One B-rep face of a CAD part: STEP entity #6673.
In plain terms, the planar face has unit normal (0, 1, 0).
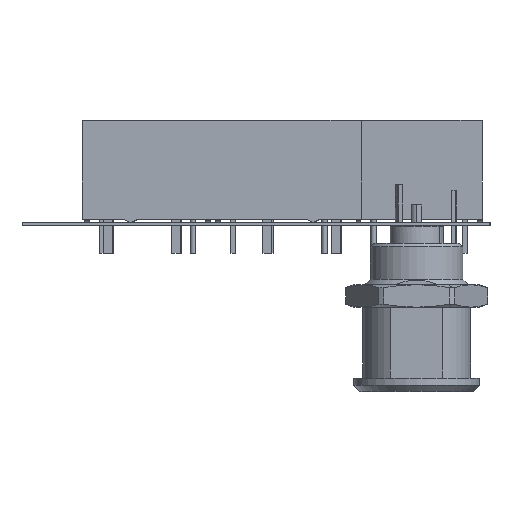
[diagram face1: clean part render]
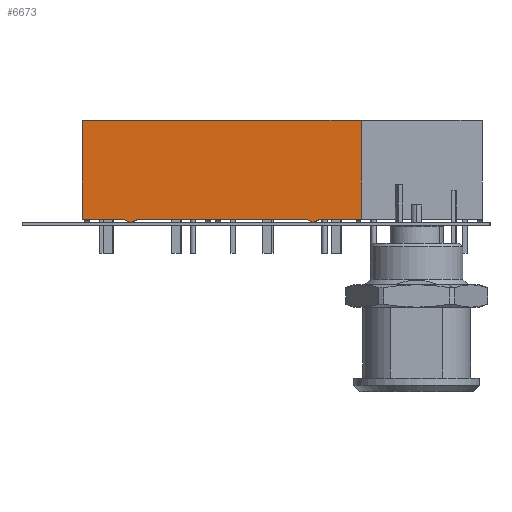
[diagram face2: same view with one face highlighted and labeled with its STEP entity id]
Its self-contained STEP definition (entity closure, numbers rounded to 3 decimals):
#4685 = EDGE_CURVE('',#4686,#4688,#4690,.T.);
#4686 = VERTEX_POINT('',#4687);
#4687 = CARTESIAN_POINT('',(15.5,7.,11.3));
#4688 = VERTEX_POINT('',#4689);
#4689 = CARTESIAN_POINT('',(-15.5,7.,11.3));
#4690 = LINE('',#4691,#4692);
#4691 = CARTESIAN_POINT('',(-15.5,7.,11.3));
#4692 = VECTOR('',#4693,1.);
#4693 = DIRECTION('',(-1.,0.,0.));
#6318 = VERTEX_POINT('',#6319);
#6319 = CARTESIAN_POINT('',(-15.5,7.,0.3));
#6325 = EDGE_CURVE('',#6318,#6326,#6328,.T.);
#6326 = VERTEX_POINT('',#6327);
#6327 = CARTESIAN_POINT('',(-10.774,7.,0.3));
#6328 = LINE('',#6329,#6330);
#6329 = CARTESIAN_POINT('',(-15.5,7.,0.3));
#6330 = VECTOR('',#6331,1.);
#6331 = DIRECTION('',(1.,0.,0.));
#6350 = VERTEX_POINT('',#6351);
#6351 = CARTESIAN_POINT('',(-9.526,7.,0.3));
#6357 = EDGE_CURVE('',#6350,#6358,#6360,.T.);
#6358 = VERTEX_POINT('',#6359);
#6359 = CARTESIAN_POINT('',(9.526,7.,0.3));
#6360 = LINE('',#6361,#6362);
#6361 = CARTESIAN_POINT('',(-9.526,7.,0.3));
#6362 = VECTOR('',#6363,1.);
#6363 = DIRECTION('',(1.,0.,0.));
#6382 = VERTEX_POINT('',#6383);
#6383 = CARTESIAN_POINT('',(10.774,7.,0.3));
#6389 = EDGE_CURVE('',#6382,#6390,#6392,.T.);
#6390 = VERTEX_POINT('',#6391);
#6391 = CARTESIAN_POINT('',(15.5,7.,0.3));
#6392 = LINE('',#6393,#6394);
#6393 = CARTESIAN_POINT('',(10.774,7.,0.3));
#6394 = VECTOR('',#6395,1.);
#6395 = DIRECTION('',(1.,0.,0.));
#6529 = EDGE_CURVE('',#6326,#6350,#6530,.T.);
#6530 = CIRCLE('',#6531,0.8);
#6531 = AXIS2_PLACEMENT_3D('',#6532,#6533,#6534);
#6532 = CARTESIAN_POINT('',(-10.15,7.,0.8));
#6533 = DIRECTION('',(0.,-1.,0.));
#6534 = DIRECTION('',(1.,0.,0.));
#6577 = EDGE_CURVE('',#6358,#6382,#6578,.T.);
#6578 = CIRCLE('',#6579,0.8);
#6579 = AXIS2_PLACEMENT_3D('',#6580,#6581,#6582);
#6580 = CARTESIAN_POINT('',(10.15,7.,0.8));
#6581 = DIRECTION('',(0.,-1.,0.));
#6582 = DIRECTION('',(1.,0.,0.));
#6617 = EDGE_CURVE('',#4688,#6318,#6618,.T.);
#6618 = LINE('',#6619,#6620);
#6619 = CARTESIAN_POINT('',(-15.5,7.,11.3));
#6620 = VECTOR('',#6621,1.);
#6621 = DIRECTION('',(0.,0.,-1.));
#6639 = EDGE_CURVE('',#6390,#4686,#6640,.T.);
#6640 = LINE('',#6641,#6642);
#6641 = CARTESIAN_POINT('',(15.5,7.,11.3));
#6642 = VECTOR('',#6643,1.);
#6643 = DIRECTION('',(0.,0.,1.));
#6673 = ADVANCED_FACE('',(#6674),#6684,.F.);
#6674 = FACE_BOUND('',#6675,.T.);
#6675 = EDGE_LOOP('',(#6676,#6677,#6678,#6679,#6680,#6681,#6682,#6683));
#6676 = ORIENTED_EDGE('',*,*,#6617,.F.);
#6677 = ORIENTED_EDGE('',*,*,#4685,.F.);
#6678 = ORIENTED_EDGE('',*,*,#6639,.F.);
#6679 = ORIENTED_EDGE('',*,*,#6389,.F.);
#6680 = ORIENTED_EDGE('',*,*,#6577,.F.);
#6681 = ORIENTED_EDGE('',*,*,#6357,.F.);
#6682 = ORIENTED_EDGE('',*,*,#6529,.F.);
#6683 = ORIENTED_EDGE('',*,*,#6325,.F.);
#6684 = PLANE('',#6685);
#6685 = AXIS2_PLACEMENT_3D('',#6686,#6687,#6688);
#6686 = CARTESIAN_POINT('',(-10.15,7.,0.8));
#6687 = DIRECTION('',(0.,-1.,0.));
#6688 = DIRECTION('',(1.,0.,0.));
